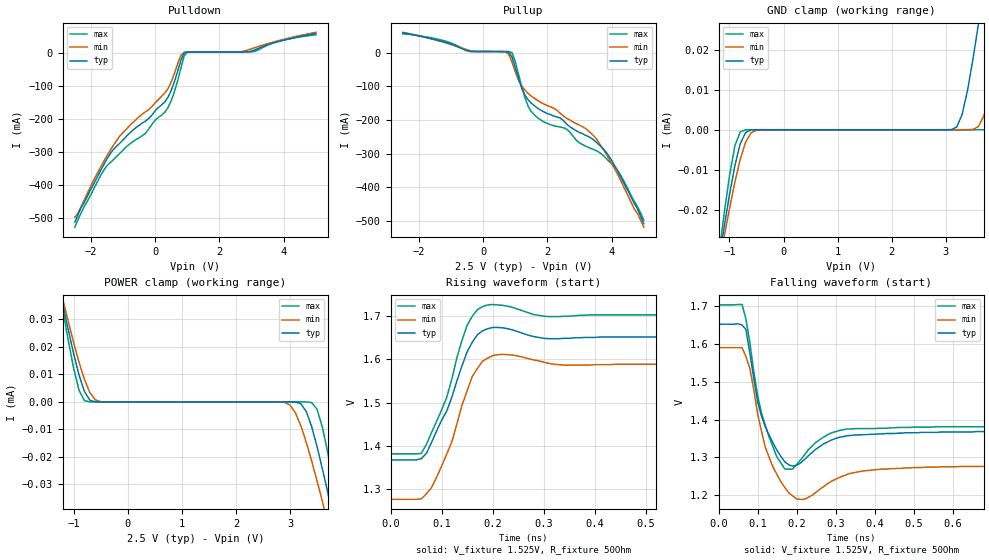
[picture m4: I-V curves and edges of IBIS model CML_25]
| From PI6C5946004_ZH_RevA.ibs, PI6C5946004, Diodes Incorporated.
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| Model  OUTPUT LVDS_25
[Model]  CML_25
Model_type  Output
Vmeas =   1.3
|Variable   typ   min   max
C_comp   1.93p   1.91p  1.96p
|Variable   typ   min   max
[Voltage Range]   2.5   2.375   2.625
[Temperature Range]   25   85   -40
[Pullup Reference]   2.5   2.375   2.625
[Pulldown Reference]   0   0   0
[Power Clamp Reference]   2.5   2.375   2.625
[GND Clamp Reference]   0   0   0
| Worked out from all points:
|   slope of the pulldown table from 0 to 0.375 V, typ, clamps not added: 10 ohm
|   slope of the pullup table from 0 to 0.375 V, typ, clamps not added: 5.77 kohm
|   falling waveform, V_fixture 1.525V, R_fixture 50Ohm: 20-80 % time 28.9ps typ, 35.3ps min, 29.4ps max; typ from 1.65 V to 1.37 V
|   rising waveform, V_fixture 1.525V, R_fixture 50Ohm: 20-80 % time 56.7ps typ, 55.4ps min, 52.6ps max; typ from 1.37 V to 1.65 V
[GND Clamp]
| Voltage   I(typ)   I(min)  I(max)
-2.5V     -159uA     -141uA     -188uA
-1.2V     -33.2uA    -34.4uA    -31.9uA
-1.1V     -24.5uA    -26.9uA    -21.2uA
-900mV    -9uA       -13.1uA    -4.02uA
-700mV    -692nA     -3.07uA    -12.5nA
3.2V      664nA      15.6pA     5.6pA
3.6V      26.3uA     787nA      7.2pA
4.1V      75.3uA     29.3uA     9.75pA
4.4V      106uA      54.1uA     451nA
4.5V      117uA      62.6uA     4.28uA
4.7V      138uA      80.1uA     22.5uA
5V        170uA      107uA      57.4uA
[POWER Clamp]
| Voltage   I(typ)   I(min)  I(max)
-2.5V     170uA      152uA      197uA
-1.3V     45.2uA     45.6uA     45.3uA
-1.2V     35.6uA     37.3uA     33.6uA
-1V       17.6uA     21.6uA     12.3uA
-800mV    3.79uA     8.18uA     451nA
-500mV    983pA      78.9nA     7.8pA
2.9V      -37.3pA    -183nA     -6.35pA
3.1V      -51nA      -3.97uA    -7.34pA
3.4V      -9uA       -21.5uA    -239nA
3.6V      -24.5uA    -36.3uA    -9.41uA
3.9V      -51.5uA    -60uA      -40.2uA
5V        -159uA     -152uA     -173uA
[Pulldown]
| Voltage   I(typ)   I(min)  I(max)
-2.5V     -512mA     -497mA     -527mA
-1.7V     -356mA     -346mA     -371mA
-1.4V     -305mA     -295mA     -332mA
-1.1V     -273mA     -251mA     -304mA
-300mV    -206mA     -178mA     -243mA
400mV     -134mA     -108mA     -165mA
600mV     -86.5mA    -61.4mA    -117mA
800mV     -21.8mA    -7.34mA    -46mA
900mV     47.2uA     2.17mA     -9.46mA
1V        2.98mA     2.98mA     2.82mA
2.9V      3.59mA     9.66mA     3.41mA
5V        58.7mA     62.5mA     54.9mA
[Pullup]   |Note: Vtable = Vcc - Voutput
| Voltage   I(typ)   I(min)  I(max)
-2.5V     58.7mA     60.3mA     55.3mA
-1.3V     33.7mA     33.1mA     37.4mA
-400mV    3.59mA     6.07mA     3.5mA
700mV     3.15mA     2.44mA     3.23mA
900mV     -13.5mA    -28.4mA    -18uA
1.2V      -105mA     -98.6mA    -100mA
1.5V      -150mA     -129mA     -175mA
2.6V      -212mA     -195mA     -227mA
3V        -237mA     -215mA     -268mA
3.5V      -264mA     -253mA     -290mA
4.2V      -354mA     -364mA     -352mA
5V        -508mA     -518mA     -497mA
[Falling Waveform]
V_fixture = 1.525V
V_fixture_min = 1.432V
V_fixture_max = 1.540V
R_fixture = 50Ohm
C_fixture = 0F
|   Time   V(typ)   V(min)   V(max)
0s        1.652V     1.59V      1.703V
60ps      1.65V      1.59V      1.704V
70ps      1.638V     1.567V     1.666V
100ps     1.447V     1.415V     1.464V
110ps     1.409V     1.369V     1.417V
140ps     1.337V     1.273V     1.326V
170ps     1.288V     1.22V      1.269V
220ps     1.294V     1.189V     1.306V
330ps     1.357V     1.255V     1.375V
990ps     1.368V     1.277V     1.382V
[Rising Waveform]
V_fixture = 1.525V
V_fixture_min = 1.431V
V_fixture_max = 1.540V
R_fixture = 50Ohm
C_fixture = 0F
|   Time   V(typ)   V(min)   V(max)
0s        1.368V     1.277V     1.382V
60ps      1.371V     1.278V     1.383V
80ps      1.408V     1.304V     1.431V
110ps     1.481V     1.382V     1.513V
150ps     1.618V     1.528V     1.679V
160ps     1.64V      1.561V     1.7V
190ps     1.671V     1.603V     1.726V
240ps     1.668V     1.61V      1.72V
310ps     1.648V     1.591V     1.699V
990ps     1.652V     1.59V      1.703V
[Ramp]
|   typ   min   max
dV/dt_r   0.226/43.21E-12   0.240V/44.22E-12   0.247V/38.60E-12
dV/dt_f   0.226/31.43E-12   0.240V/34.63E-12   0.247V/28.79E-12
R_load =   50.0000
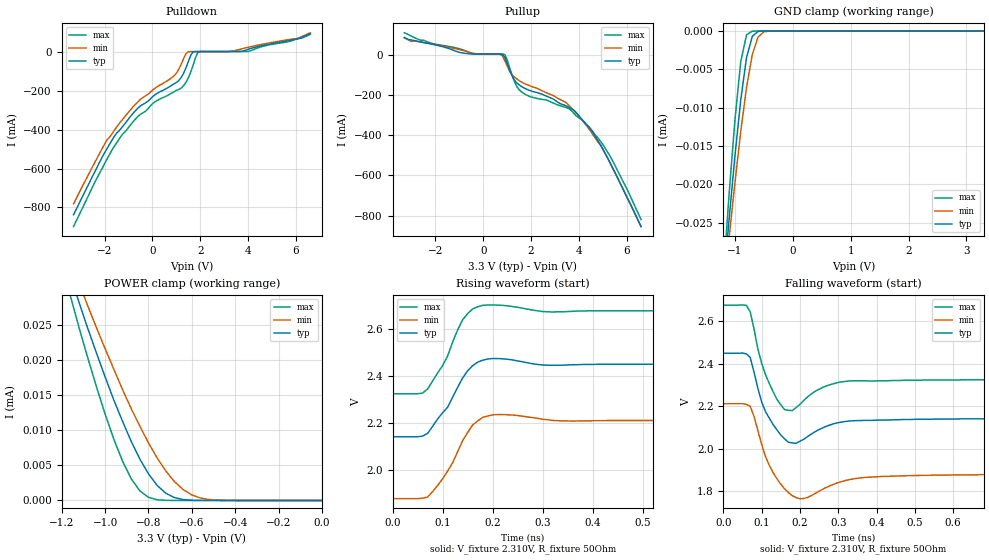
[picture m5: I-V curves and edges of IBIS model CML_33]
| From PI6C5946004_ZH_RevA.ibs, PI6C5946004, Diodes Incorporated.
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| Model  OUTPUT LVDS_33
[Model]  CML_33
Model_type  Output
Vmeas =  2.2
Rref = 50
|Variable   typ   min   max
C_comp   1.93p   1.91p  1.96p
|Variable   typ   min   max
[Voltage Range]   3.3   3.0   3.6
[Temperature Range]   25   85   -40
[Pullup Reference]   3.3   3.0   3.6
[Pulldown Reference]   0   0   0
[Power Clamp Reference]   3.3   3.0   3.6
[GND Clamp Reference]   0   0   0
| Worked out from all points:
|   slope of the pulldown table from 0 to 0.495 V, typ, clamps not added: 13.5 ohm
|   slope of the pullup table from 0 to 0.495 V, typ, clamps not added: 6.23 kohm
|   falling waveform, V_fixture 2.310V, R_fixture 50Ohm: 20-80 % time 27.5ps typ, 33.1ps min, 26.6ps max; typ from 2.45 V to 2.14 V
|   rising waveform, V_fixture 2.310V, R_fixture 50Ohm: 20-80 % time 53.5ps typ, 52.1ps min, 47.7ps max; typ from 2.14 V to 2.45 V
[gnd clamp]
-3.3V     -239uA     -209uA     -287uA
-1.2V     -33.2uA    -34.4uA    -31.9uA
-1.1V     -24.5uA    -26.9uA    -21.2uA
-1V       -16.3uA    -19.8uA    -11.6uA
-900mV    -9uA       -13.1uA    -4.02uA
-800mV    -3.48uA    -7.37uA    -510nA
-700mV    -692nA     -3.07uA    -12.5nA
-600mV    -51nA      -785nA     -109pA
-500mV    -1.49nA    -102nA     -9.86pA
-400mV    -38.9pA    -6.45nA    -8.8pA
3.3V      6.6pA      207pA      6pA
[power clamp]
-3.28V    253uA      224uA      299uA
-1.16V    31.8uA     34.1uA     29.1uA
-1.12V    28.2uA     30.9uA     24.6uA
-1.08V    24.5uA     27.7uA     20.3uA
-1V       17.6uA     21.6uA     12.3uA
-920mV    11.3uA     15.8uA     5.62uA
-840mV    5.91uA     10.6uA     1.38uA
-800mV    3.79uA     8.18uA     451nA
-760mV    2.14uA     6.04uA     105nA
-680mV    406nA      2.68uA     3.06nA
-560mV    8.78nA     347nA      19.3pA
0V        6.6pA      6.02pA     7.2pA
[Pulldown]
| Voltage   I(typ)   I(min)  I(max)
-3.3V     -838mA     -782mA     -899mA
-2V       -518mA     -474mA     -574mA
-1.5V     -417mA     -386mA     -468mA
-600mV    -287mA     -255mA     -330mA
0V        -230mA     -196mA     -266mA
900mV     -163mA     -122mA     -204mA
1.3V      -109mA     -34.1mA    -173mA
1.6V      -16.2mA    3.16mA     -103mA
1.9V      3.31mA     3.25mA     109uA
4V        14.6mA     25.2mA     4.12mA
6V        69.1mA     65.7mA     67.7mA
6.6V      95.7mA     100mA      92.1mA
[Pullup]   |Note: Vtable = Vcc - Voutput
| Voltage   I(typ)   I(min)  I(max)
-3.3V     85.7mA     83.7mA     109mA
-400mV    3.57mA     6.82mA     4.12mA
800mV     1.95mA     -5.37mA    3.49mA
1V        -43.7mA    -56.2mA    -25.9mA
1.3V      -126mA     -111mA     -132mA
1.6V      -158mA     -136mA     -185mA
3.5V      -256mA     -242mA     -264mA
3.8V      -277mA     -279mA     -293mA
4.5V      -372mA     -382mA     -371mA
5V        -469mA     -470mA     -447mA
5.5V      -585mA     -585mA     -549mA
6.6V      -855mA     -855mA     -820mA
[Falling Waveform]
V_fixture = 2.310V
V_fixture_min = 2.043V
V_fixture_max = 2.497V
R_fixture = 50Ohm
C_fixture = 0F
|   Time   V(typ)   V(min)   V(max)
0s        2.449V     2.212V     2.675V
60ps      2.446V     2.209V     2.674V
70ps      2.43V      2.2V       2.644V
90ps      2.285V     2.087V     2.47V
110ps     2.175V     1.964V     2.349V
160ps     2.047V     1.812V     2.184V
210ps     2.045V     1.767V     2.227V
260ps     2.099V     1.811V     2.289V
330ps     2.131V     1.856V     2.319V
990ps     2.142V     1.88V      2.324V
[Rising Waveform]
V_fixture = 2.310V
V_fixture_min = 2.043V
V_fixture_max = 2.497V
R_fixture = 50Ohm
C_fixture = 0F
|   Time   V(typ)   V(min)   V(max)
0s        2.142V     1.88V      2.324V
50ps      2.142V     1.88V      2.324V
70ps      2.156V     1.887V     2.344V
110ps     2.267V     1.997V     2.484V
140ps     2.391V     2.126V     2.637V
160ps     2.443V     2.192V     2.683V
180ps     2.466V     2.224V     2.698V
220ps     2.472V     2.236V     2.698V
320ps     2.445V     2.211V     2.67V
990ps     2.449V     2.212V     2.675V
[Ramp]
|   typ   min   max
dV/dt_r   0.243/41.28E-12   0.275/42.73E-12   0.263/37.17E-12
dV/dt_f   0.243/29.10E-12   0.275/33.39E-12   0.263/26.54E-12
R_load =   50.0000
